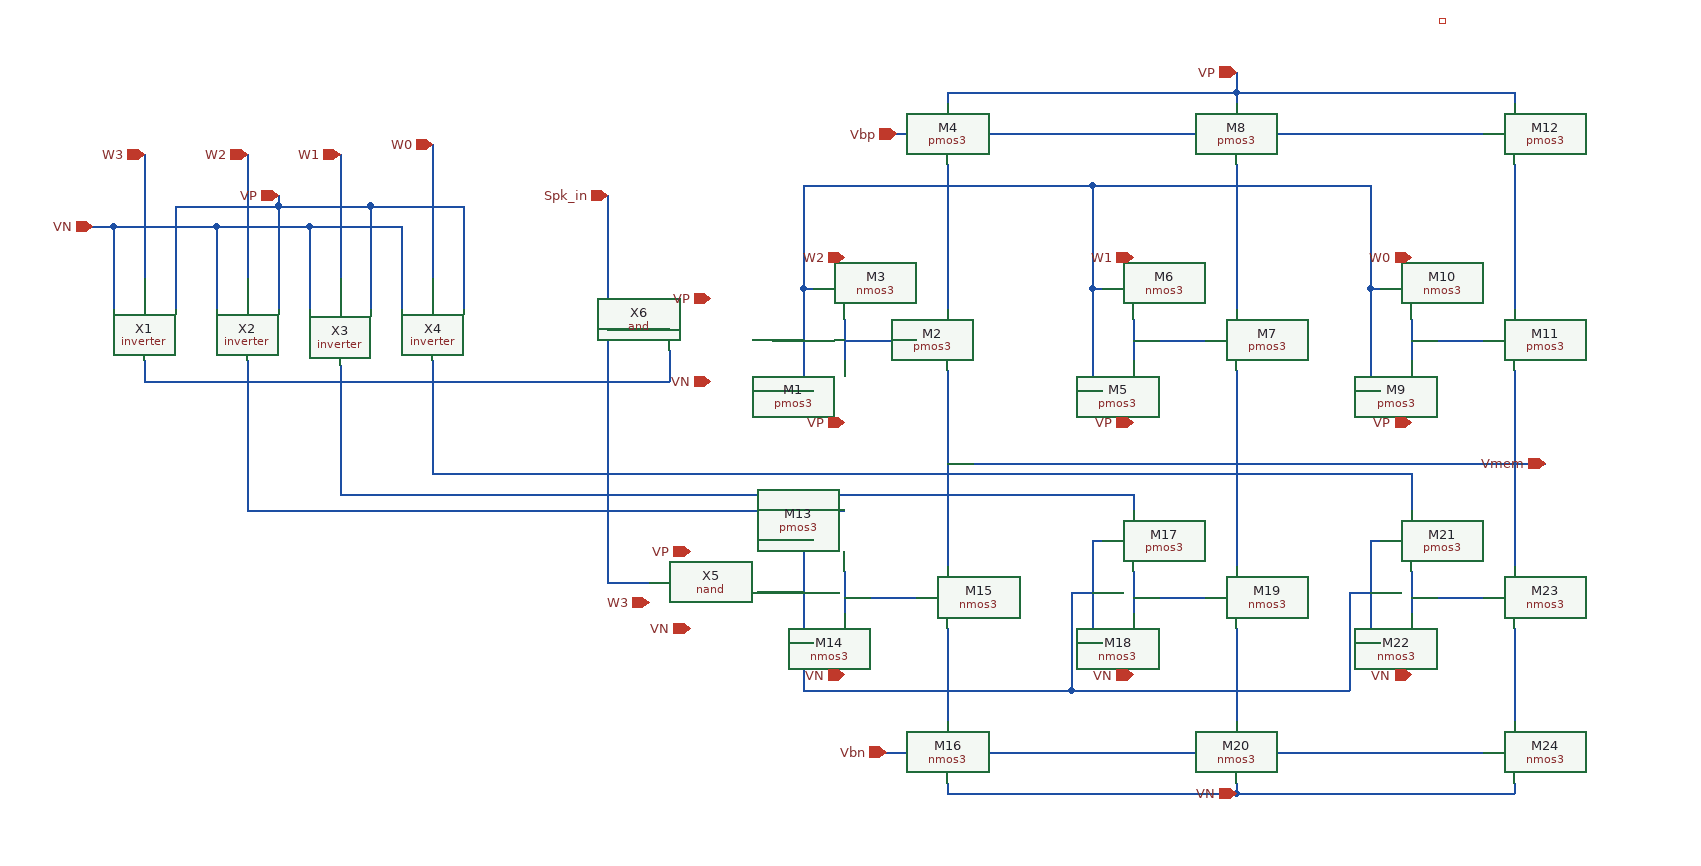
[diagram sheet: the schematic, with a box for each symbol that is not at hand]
v {xschem version=3.4.3 file_version=1.2
}
G {}
K {}
V {}
S {A low power spiking neural network chip based on a compact LIF Neuron and Binary Exponential Chrage Injector Synapse Circuits}
E {}
B 5 1167.5 -422.5 1172.5 -417.5 {name=VP
dir=inout}
N 220 -230 220 -140 {
lab=VP}
N 130 -240 130 -140 {
lab=VP}
N 130 -240 220 -240 {
lab=VP}
N 220 -240 220 -230 {
lab=VP}
N 50 -240 130 -240 {
lab=VP}
N 40 -240 40 -140 {
lab=VP}
N 40 -240 50 -240 {
lab=VP}
N -50 -240 40 -240 {
lab=VP}
N -60 -240 -50 -240 {
lab=VP}
N -60 -240 -60 -140 {
lab=VP}
N -120 -220 -120 -140 {
lab=VN}
N -120 -220 -20 -220 {
lab=VN}
N -20 -220 -20 -140 {
lab=VN}
N -20 -220 70 -220 {
lab=VN}
N 70 -220 70 -140 {
lab=VN}
N 70 -220 160 -220 {
lab=VN}
N 160 -220 160 -140 {
lab=VN}
N -140 -220 -120 -220 {
lab=VN}
N 360 125 375 125 {
lab=Spk_in}
N 360 -20 360 125 {
lab=Spk_in}
N 360 -250 360 -20 {
lab=Spk_in}
N -90 -290 -90 -170 {
lab=W3}
N 10 -290 10 -170 {
lab=W2}
N 100 -290 100 -170 {
lab=W1}
N 190 -300 190 -170 {
lab=W0}
N 360 -120 420 -120 {
lab=Spk_in}
N -90 -90 -90 -70 {
lab=#net1}
N -90 -70 420 -70 {
lab=#net1}
N 420 -100 420 -70 {
lab=#net1}
N 550 -160 560 -160 {
lab=#net2}
N 550 -160 550 -60 {
lab=#net2}
N 550 -60 560 -60 {
lab=#net2}
N 590 -130 590 -90 {
lab=#net3}
N 690 -270 690 -140 {
lab=#net4}
N 690 -280 690 -270 {
lab=#net4}
N 590 -110 660 -110 {
lab=#net3}
N 830 -160 840 -160 {
lab=#net5}
N 830 -160 830 -60 {
lab=#net5}
N 830 -60 840 -60 {
lab=#net5}
N 870 -130 870 -90 {
lab=#net6}
N 970 -270 970 -140 {
lab=#net7}
N 970 -280 970 -270 {
lab=#net7}
N 870 -110 940 -110 {
lab=#net6}
N 1100 -160 1110 -160 {
lab=#net8}
N 1100 -160 1100 -60 {
lab=#net8}
N 1100 -60 1110 -60 {
lab=#net8}
N 1140 -130 1140 -90 {
lab=#net9}
N 1240 -270 1240 -140 {
lab=#net10}
N 1240 -280 1240 -270 {
lab=#net10}
N 1140 -110 1210 -110 {
lab=#net9}
N 380 125 400 125 {
lab=Spk_in}
N 375 125 380 125 {
lab=Spk_in}
N 520 -110 550 -110 {
lab=#net2}
N 550 85 560 85 {
lab=#net11}
N 550 85 550 185 {
lab=#net11}
N 550 185 560 185 {
lab=#net11}
N 590 115 590 155 {
lab=#net12}
N 500 135 530 135 {
lab=#net11}
N 530 135 550 135 {
lab=#net11}
N 640 -310 660 -310 {
lab=Vbp}
N 660 -310 940 -310 {
lab=Vbp}
N 940 -310 1210 -310 {
lab=Vbp}
N 690 -80 690 100 {
lab=VP}
N 590 140 660 140 {
lab=#net12}
N 690 100 690 110 {
lab=VP}
N 690 170 690 260 {
lab=#net13}
N 830 85 840 85 {
lab=#net11}
N 830 85 830 185 {
lab=#net11}
N 830 185 840 185 {
lab=#net11}
N 870 115 870 155 {
lab=#net14}
N 810 135 830 135 {
lab=#net11}
N 870 140 940 140 {
lab=#net14}
N 970 100 970 110 {
lab=VP}
N 970 170 970 260 {
lab=#net15}
N 970 -80 970 100 {
lab=VP}
N 1100 85 1110 85 {
lab=#net11}
N 1100 85 1100 185 {
lab=#net11}
N 1100 185 1110 185 {
lab=#net11}
N 1140 115 1140 155 {
lab=#net16}
N 1080 135 1100 135 {
lab=#net11}
N 1140 140 1210 140 {
lab=#net16}
N 1240 170 1240 260 {
lab=#net17}
N 1240 -80 1240 110 {
lab=VP}
N 630 290 660 290 {
lab=Vbn}
N 660 290 940 290 {
lab=Vbn}
N 940 290 1210 290 {
lab=Vbn}
N 690 320 690 330 {
lab=VN}
N 690 330 970 330 {
lab=VN}
N 970 320 970 330 {
lab=VN}
N 970 330 1240 330 {
lab=VN}
N 1240 320 1240 330 {
lab=VN}
N 690 -350 690 -340 {
lab=VP}
N 690 -350 970 -350 {
lab=VP}
N 970 -350 970 -340 {
lab=VP}
N 970 -350 1240 -350 {
lab=VP}
N 1240 -350 1240 -340 {
lab=VP}
N 970 -370 970 -350 {
lab=VP}
N 40 -250 40 -240 {
lab=VP}
N 550 230 810 230 {
lab=#net11}
N 810 135 810 230 {
lab=#net11}
N 1080 135 1080 230 {
lab=#net11}
N 810 230 1080 230 {
lab=#net11}
N 550 185 550 230 {
lab=#net11}
N 10 -90 10 40 {
lab=#net18}
N 10 55 590 55 {
lab=#net18}
N 10 40 10 55 {
lab=#net18}
N 870 45 870 55 {
lab=#net19}
N 870 40 870 45 {
lab=#net19}
N 100 -85 100 40 {
lab=#net19}
N 100 40 870 40 {
lab=#net19}
N 1140 25 1140 55 {
lab=#net20}
N 190 -90 190 15 {
lab=#net20}
N 190 15 190 20 {
lab=#net20}
N 190 20 1140 20 {
lab=#net20}
N 1140 20 1140 25 {
lab=#net20}
N 690 10 970 10 {
lab=VP}
N 970 10 1240 10 {
lab=VP}
N 1240 10 1270 10 {
lab=VP}
N 550 -260 550 -160 {}
N 550 -260 830 -260 {}
N 830 -260 830 -160 {}
N 830 -260 1100 -260 {}
N 1100 -260 1100 -160 {}
C {/home/madvlsi/neuromorphic_computing_final/schematic/inverter.sym} -90 -200 1 0 {name=X1}
C {/home/madvlsi/neuromorphic_computing_final/schematic/inverter.sym} 10 -200 1 0 {name=X2}
C {/home/madvlsi/neuromorphic_computing_final/schematic/inverter.sym} 100 -200 1 0 {name=X3}
C {/home/madvlsi/neuromorphic_computing_final/schematic/inverter.sym} 190 -200 1 0 {name=X4}
C {/home/madvlsi/neuromorphic_computing_final/schematic/nand.sym} 375 135 0 0 {name=X5}
C {/home/madvlsi/neuromorphic_computing_final/schematic/and.sym} 395 -110 0 0 {name=X6}
C {devices/iopin.sym} -90 -290 3 0 {name=p1 lab=W3}
C {devices/iopin.sym} 10 -290 3 0 {name=p2 lab=W2}
C {devices/iopin.sym} 100 -290 3 0 {name=p3 lab=W1}
C {devices/iopin.sym} 190 -300 3 0 {name=p4 lab=W0}
C {devices/iopin.sym} 400 145 2 0 {name=p5 lab=W3}
C {madvlsi/pmos3.sym} 590 -60 0 0 {name=M1
L=\{L\}
W=\{W\}
body=VDD
nf=1
mult=1
ad="'int((nf+1)/2) * W/nf * 0.29'" 
pd="'2*int((nf+1)/2) * (W/nf + 0.29)'"
as="'int((nf+2)/2) * W/nf * 0.29'" 
ps="'2*int((nf+2)/2) * (W/nf + 0.29)'"
nrd="'0.29 / W'" nrs="'0.29 / W'"
sa=0 sb=0 sd=0
model=pfet_01v8
spiceprefix=X
}
C {madvlsi/nmos3.sym} 590 -160 0 0 {name=M3
L=\{L\}
W=\{W\}
body=GND
nf=1
mult=1
ad="'int((nf+1)/2) * W/nf * 0.29'" 
pd="'2*int((nf+1)/2) * (W/nf + 0.29)'"
as="'int((nf+2)/2) * W/nf * 0.29'" 
ps="'2*int((nf+2)/2) * (W/nf + 0.29)'"
nrd="'0.29 / W'" nrs="'0.29 / W'"
sa=0 sb=0 sd=0
model=nfet_01v8
spiceprefix=X
}
C {madvlsi/pmos3.sym} 690 -110 0 0 {name=M2
L=\{L\}
W=\{W\}
body=VDD
nf=1
mult=1
ad="'int((nf+1)/2) * W/nf * 0.29'" 
pd="'2*int((nf+1)/2) * (W/nf + 0.29)'"
as="'int((nf+2)/2) * W/nf * 0.29'" 
ps="'2*int((nf+2)/2) * (W/nf + 0.29)'"
nrd="'0.29 / W'" nrs="'0.29 / W'"
sa=0 sb=0 sd=0
model=pfet_01v8
spiceprefix=X
}
C {madvlsi/pmos3.sym} 690 -310 0 0 {name=M4
L=\{L\}
W=\{W\}
body=VDD
nf=1
mult=4
ad="'int((nf+1)/2) * W/nf * 0.29'" 
pd="'2*int((nf+1)/2) * (W/nf + 0.29)'"
as="'int((nf+2)/2) * W/nf * 0.29'" 
ps="'2*int((nf+2)/2) * (W/nf + 0.29)'"
nrd="'0.29 / W'" nrs="'0.29 / W'"
sa=0 sb=0 sd=0
model=pfet_01v8
spiceprefix=X
}
C {madvlsi/pmos3.sym} 870 -60 0 0 {name=M5
L=\{L\}
W=\{W\}
body=VDD
nf=1
mult=1
ad="'int((nf+1)/2) * W/nf * 0.29'" 
pd="'2*int((nf+1)/2) * (W/nf + 0.29)'"
as="'int((nf+2)/2) * W/nf * 0.29'" 
ps="'2*int((nf+2)/2) * (W/nf + 0.29)'"
nrd="'0.29 / W'" nrs="'0.29 / W'"
sa=0 sb=0 sd=0
model=pfet_01v8
spiceprefix=X
}
C {madvlsi/nmos3.sym} 870 -160 0 0 {name=M6
L=\{L\}
W=\{W\}
body=GND
nf=1
mult=1
ad="'int((nf+1)/2) * W/nf * 0.29'" 
pd="'2*int((nf+1)/2) * (W/nf + 0.29)'"
as="'int((nf+2)/2) * W/nf * 0.29'" 
ps="'2*int((nf+2)/2) * (W/nf + 0.29)'"
nrd="'0.29 / W'" nrs="'0.29 / W'"
sa=0 sb=0 sd=0
model=nfet_01v8
spiceprefix=X
}
C {madvlsi/pmos3.sym} 970 -110 0 0 {name=M7
L=\{L\}
W=\{W\}
body=VDD
nf=1
mult=1
ad="'int((nf+1)/2) * W/nf * 0.29'" 
pd="'2*int((nf+1)/2) * (W/nf + 0.29)'"
as="'int((nf+2)/2) * W/nf * 0.29'" 
ps="'2*int((nf+2)/2) * (W/nf + 0.29)'"
nrd="'0.29 / W'" nrs="'0.29 / W'"
sa=0 sb=0 sd=0
model=pfet_01v8
spiceprefix=X
}
C {madvlsi/pmos3.sym} 970 -310 0 0 {name=M8
L=\{L\}
W=\{W\}
body=VDD
nf=1
mult=2
ad="'int((nf+1)/2) * W/nf * 0.29'" 
pd="'2*int((nf+1)/2) * (W/nf + 0.29)'"
as="'int((nf+2)/2) * W/nf * 0.29'" 
ps="'2*int((nf+2)/2) * (W/nf + 0.29)'"
nrd="'0.29 / W'" nrs="'0.29 / W'"
sa=0 sb=0 sd=0
model=pfet_01v8
spiceprefix=X
}
C {madvlsi/pmos3.sym} 1140 -60 0 0 {name=M9
L=\{L\}
W=\{W\}
body=VDD
nf=1
mult=1
ad="'int((nf+1)/2) * W/nf * 0.29'" 
pd="'2*int((nf+1)/2) * (W/nf + 0.29)'"
as="'int((nf+2)/2) * W/nf * 0.29'" 
ps="'2*int((nf+2)/2) * (W/nf + 0.29)'"
nrd="'0.29 / W'" nrs="'0.29 / W'"
sa=0 sb=0 sd=0
model=pfet_01v8
spiceprefix=X
}
C {madvlsi/nmos3.sym} 1140 -160 0 0 {name=M10
L=\{L\}
W=\{W\}
body=GND
nf=1
mult=1
ad="'int((nf+1)/2) * W/nf * 0.29'" 
pd="'2*int((nf+1)/2) * (W/nf + 0.29)'"
as="'int((nf+2)/2) * W/nf * 0.29'" 
ps="'2*int((nf+2)/2) * (W/nf + 0.29)'"
nrd="'0.29 / W'" nrs="'0.29 / W'"
sa=0 sb=0 sd=0
model=nfet_01v8
spiceprefix=X
}
C {madvlsi/pmos3.sym} 1240 -110 0 0 {name=M11
L=\{L\}
W=\{W\}
body=VDD
nf=1
mult=1
ad="'int((nf+1)/2) * W/nf * 0.29'" 
pd="'2*int((nf+1)/2) * (W/nf + 0.29)'"
as="'int((nf+2)/2) * W/nf * 0.29'" 
ps="'2*int((nf+2)/2) * (W/nf + 0.29)'"
nrd="'0.29 / W'" nrs="'0.29 / W'"
sa=0 sb=0 sd=0
model=pfet_01v8
spiceprefix=X
}
C {madvlsi/pmos3.sym} 1240 -310 0 0 {name=M12
L=\{L\}
W=\{W\}
body=VDD
nf=1
mult=1
ad="'int((nf+1)/2) * W/nf * 0.29'" 
pd="'2*int((nf+1)/2) * (W/nf + 0.29)'"
as="'int((nf+2)/2) * W/nf * 0.29'" 
ps="'2*int((nf+2)/2) * (W/nf + 0.29)'"
nrd="'0.29 / W'" nrs="'0.29 / W'"
sa=0 sb=0 sd=0
model=pfet_01v8
spiceprefix=X
}
C {madvlsi/pmos3.sym} 590 85 0 0 {name=M13
L=\{L\}
W=\{W\}
body=VDD
nf=1
mult=1
ad="'int((nf+1)/2) * W/nf * 0.29'" 
pd="'2*int((nf+1)/2) * (W/nf + 0.29)'"
as="'int((nf+2)/2) * W/nf * 0.29'" 
ps="'2*int((nf+2)/2) * (W/nf + 0.29)'"
nrd="'0.29 / W'" nrs="'0.29 / W'"
sa=0 sb=0 sd=0
model=pfet_01v8
spiceprefix=X
}
C {madvlsi/nmos3.sym} 590 185 0 0 {name=M14
L=\{L\}
W=\{W\}
body=GND
nf=1
mult=1
ad="'int((nf+1)/2) * W/nf * 0.29'" 
pd="'2*int((nf+1)/2) * (W/nf + 0.29)'"
as="'int((nf+2)/2) * W/nf * 0.29'" 
ps="'2*int((nf+2)/2) * (W/nf + 0.29)'"
nrd="'0.29 / W'" nrs="'0.29 / W'"
sa=0 sb=0 sd=0
model=nfet_01v8
spiceprefix=X
}
C {madvlsi/nmos3.sym} 690 140 0 0 {name=M15
L=\{L\}
W=\{W\}
body=GND
nf=1
mult=1
ad="'int((nf+1)/2) * W/nf * 0.29'" 
pd="'2*int((nf+1)/2) * (W/nf + 0.29)'"
as="'int((nf+2)/2) * W/nf * 0.29'" 
ps="'2*int((nf+2)/2) * (W/nf + 0.29)'"
nrd="'0.29 / W'" nrs="'0.29 / W'"
sa=0 sb=0 sd=0
model=nfet_01v8
spiceprefix=X
}
C {madvlsi/nmos3.sym} 690 290 0 0 {name=M16
L=\{L\}
W=\{W\}
body=GND
nf=1
mult=4
ad="'int((nf+1)/2) * W/nf * 0.29'" 
pd="'2*int((nf+1)/2) * (W/nf + 0.29)'"
as="'int((nf+2)/2) * W/nf * 0.29'" 
ps="'2*int((nf+2)/2) * (W/nf + 0.29)'"
nrd="'0.29 / W'" nrs="'0.29 / W'"
sa=0 sb=0 sd=0
model=nfet_01v8
spiceprefix=X
}
C {madvlsi/pmos3.sym} 870 85 0 0 {name=M17
L=\{L\}
W=\{W\}
body=VDD
nf=1
mult=1
ad="'int((nf+1)/2) * W/nf * 0.29'" 
pd="'2*int((nf+1)/2) * (W/nf + 0.29)'"
as="'int((nf+2)/2) * W/nf * 0.29'" 
ps="'2*int((nf+2)/2) * (W/nf + 0.29)'"
nrd="'0.29 / W'" nrs="'0.29 / W'"
sa=0 sb=0 sd=0
model=pfet_01v8
spiceprefix=X
}
C {madvlsi/nmos3.sym} 870 185 0 0 {name=M18
L=\{L\}
W=\{W\}
body=GND
nf=1
mult=1
ad="'int((nf+1)/2) * W/nf * 0.29'" 
pd="'2*int((nf+1)/2) * (W/nf + 0.29)'"
as="'int((nf+2)/2) * W/nf * 0.29'" 
ps="'2*int((nf+2)/2) * (W/nf + 0.29)'"
nrd="'0.29 / W'" nrs="'0.29 / W'"
sa=0 sb=0 sd=0
model=nfet_01v8
spiceprefix=X
}
C {madvlsi/nmos3.sym} 970 140 0 0 {name=M19
L=\{L\}
W=\{W\}
body=GND
nf=1
mult=1
ad="'int((nf+1)/2) * W/nf * 0.29'" 
pd="'2*int((nf+1)/2) * (W/nf + 0.29)'"
as="'int((nf+2)/2) * W/nf * 0.29'" 
ps="'2*int((nf+2)/2) * (W/nf + 0.29)'"
nrd="'0.29 / W'" nrs="'0.29 / W'"
sa=0 sb=0 sd=0
model=nfet_01v8
spiceprefix=X
}
C {madvlsi/nmos3.sym} 970 290 0 0 {name=M20
L=\{L\}
W=\{W\}
body=GND
nf=1
mult=2
ad="'int((nf+1)/2) * W/nf * 0.29'" 
pd="'2*int((nf+1)/2) * (W/nf + 0.29)'"
as="'int((nf+2)/2) * W/nf * 0.29'" 
ps="'2*int((nf+2)/2) * (W/nf + 0.29)'"
nrd="'0.29 / W'" nrs="'0.29 / W'"
sa=0 sb=0 sd=0
model=nfet_01v8
spiceprefix=X
}
C {madvlsi/pmos3.sym} 1140 85 0 0 {name=M21
L=\{L\}
W=\{W\}
body=VDD
nf=1
mult=1
ad="'int((nf+1)/2) * W/nf * 0.29'" 
pd="'2*int((nf+1)/2) * (W/nf + 0.29)'"
as="'int((nf+2)/2) * W/nf * 0.29'" 
ps="'2*int((nf+2)/2) * (W/nf + 0.29)'"
nrd="'0.29 / W'" nrs="'0.29 / W'"
sa=0 sb=0 sd=0
model=pfet_01v8
spiceprefix=X
}
C {madvlsi/nmos3.sym} 1140 185 0 0 {name=M22
L=\{L\}
W=\{W\}
body=GND
nf=1
mult=1
ad="'int((nf+1)/2) * W/nf * 0.29'" 
pd="'2*int((nf+1)/2) * (W/nf + 0.29)'"
as="'int((nf+2)/2) * W/nf * 0.29'" 
ps="'2*int((nf+2)/2) * (W/nf + 0.29)'"
nrd="'0.29 / W'" nrs="'0.29 / W'"
sa=0 sb=0 sd=0
model=nfet_01v8
spiceprefix=X
}
C {madvlsi/nmos3.sym} 1240 140 0 0 {name=M23
L=\{L\}
W=\{W\}
body=GND
nf=1
mult=1
ad="'int((nf+1)/2) * W/nf * 0.29'" 
pd="'2*int((nf+1)/2) * (W/nf + 0.29)'"
as="'int((nf+2)/2) * W/nf * 0.29'" 
ps="'2*int((nf+2)/2) * (W/nf + 0.29)'"
nrd="'0.29 / W'" nrs="'0.29 / W'"
sa=0 sb=0 sd=0
model=nfet_01v8
spiceprefix=X
}
C {madvlsi/nmos3.sym} 1240 290 0 0 {name=M24
L=\{L\}
W=\{W\}
body=GND
nf=1
mult=1
ad="'int((nf+1)/2) * W/nf * 0.29'" 
pd="'2*int((nf+1)/2) * (W/nf + 0.29)'"
as="'int((nf+2)/2) * W/nf * 0.29'" 
ps="'2*int((nf+2)/2) * (W/nf + 0.29)'"
nrd="'0.29 / W'" nrs="'0.29 / W'"
sa=0 sb=0 sd=0
model=nfet_01v8
spiceprefix=X
}
C {devices/iopin.sym} 640 -310 2 0 {name=p6 lab=Vbp}
C {devices/iopin.sym} 630 290 2 0 {name=p7 lab=Vbn}
C {devices/iopin.sym} 590 -190 3 0 {name=p8 lab=W2}
C {devices/iopin.sym} 870 -190 3 0 {name=p9 lab=W1}
C {devices/iopin.sym} 1140 -190 3 0 {name=p10 lab=W0}
C {devices/iopin.sym} 870 -30 1 0 {name=p11 lab=VP}
C {devices/iopin.sym} 590 -30 1 0 {name=p12 lab=VP}
C {devices/iopin.sym} 1140 -30 1 0 {name=p13 lab=VP}
C {devices/iopin.sym} 970 -370 3 0 {name=p14 lab=VP}
C {devices/iopin.sym} 40 -250 3 0 {name=p15 lab=VP}
C {devices/iopin.sym} -140 -220 1 0 {name=p16 lab=VN}
C {devices/iopin.sym} 460 -70 1 0 {name=p17 lab=VN}
C {devices/iopin.sym} 440 170 1 0 {name=p18 lab=VN}
C {devices/iopin.sym} 970 330 1 0 {name=p20 lab=VN}
C {devices/iopin.sym} 590 215 1 0 {name=p19 lab=VN}
C {devices/iopin.sym} 870 215 1 0 {name=p21 lab=VN}
C {devices/iopin.sym} 1140 215 1 0 {name=p22 lab=VN}
C {devices/iopin.sym} 460 -150 3 0 {name=p23 lab=VP}
C {devices/iopin.sym} 440 95 3 0 {name=p24 lab=VP}
C {devices/iopin.sym} 360 -250 3 0 {name=p25 lab=Spk_in}
C {devices/iopin.sym} 1270 10 0 0 {name=p26 lab=Vmem}
